VERSION 5.7 ;
  NOWIREEXTENSIONATPIN ON ;
  DIVIDERCHAR "/" ;
  BUSBITCHARS "[]" ;
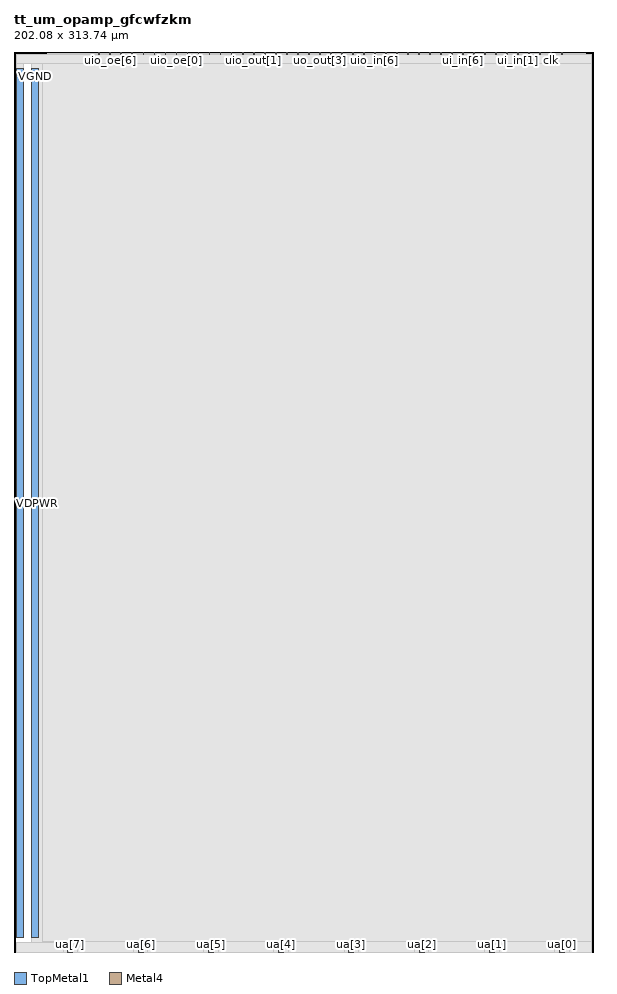
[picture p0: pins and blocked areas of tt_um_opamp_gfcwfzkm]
MACRO tt_um_opamp_gfcwfzkm
  CLASS BLOCK ;
  FOREIGN tt_um_opamp_gfcwfzkm ;
  ORIGIN 0.000 0.000 ;
  SIZE 202.080 BY 313.740 ;
  PIN ua[0]
    ANTENNAGATEAREA 1499.839966 ;
    ANTENNADIFFAREA 474.417999 ;
    PORT
      LAYER TopMetal1 ;
        RECT 190.165 0.000 191.915 2.000 ;
    END
  END ua[0]
  PIN ua[1]
    ANTENNAGATEAREA 2.160000 ;
    ANTENNADIFFAREA 147.899994 ;
    PORT
      LAYER TopMetal1 ;
        RECT 165.685 0.000 167.435 2.000 ;
    END
  END ua[1]
  PIN ua[2]
    ANTENNAGATEAREA 4.320000 ;
    PORT
      LAYER TopMetal1 ;
        RECT 141.205 0.000 142.955 2.000 ;
    END
  END ua[2]
  PIN ua[3]
    PORT
      LAYER TopMetal1 ;
        RECT 116.725 0.000 118.475 2.000 ;
    END
  END ua[3]
  PIN ua[4]
    PORT
      LAYER TopMetal1 ;
        RECT 92.245 0.000 93.995 2.000 ;
    END
  END ua[4]
  PIN ua[5]
    PORT
      LAYER TopMetal1 ;
        RECT 67.765 0.000 69.515 2.000 ;
    END
  END ua[5]
  PIN ua[6]
    PORT
      LAYER TopMetal1 ;
        RECT 43.285 0.000 45.035 2.000 ;
    END
  END ua[6]
  PIN ua[7]
    PORT
      LAYER TopMetal1 ;
        RECT 18.805 0.000 20.555 2.000 ;
    END
  END ua[7]
  PIN VDPWR
    ANTENNADIFFAREA 31.673199 ;
    PORT
      LAYER TopMetal1 ;
        RECT 1.000 5.000 3.400 308.000 ;
    END
  END VDPWR
  PIN VGND
    ANTENNAGATEAREA 168.959991 ;
    ANTENNADIFFAREA 1001.514404 ;
    PORT
      LAYER TopMetal1 ;
        RECT 6.000 5.000 8.400 308.000 ;
    END
  END VGND
  PIN clk
    PORT
      LAYER Metal4 ;
        RECT 187.050 312.740 187.350 313.740 ;
    END
  END clk
  PIN ena
    PORT
      LAYER Metal4 ;
        RECT 190.890 312.740 191.190 313.740 ;
    END
  END ena
  PIN rst_n
    PORT
      LAYER Metal4 ;
        RECT 183.210 312.740 183.510 313.740 ;
    END
  END rst_n
  PIN ui_in[0]
    ANTENNAGATEAREA 0.058500 ;
    PORT
      LAYER Metal4 ;
        RECT 179.370 312.740 179.670 313.740 ;
    END
  END ui_in[0]
  PIN ui_in[1]
    ANTENNAGATEAREA 0.058500 ;
    PORT
      LAYER Metal4 ;
        RECT 175.530 312.740 175.830 313.740 ;
    END
  END ui_in[1]
  PIN ui_in[2]
    ANTENNAGATEAREA 0.058500 ;
    PORT
      LAYER Metal4 ;
        RECT 171.690 312.740 171.990 313.740 ;
    END
  END ui_in[2]
  PIN ui_in[3]
    ANTENNAGATEAREA 0.058500 ;
    PORT
      LAYER Metal4 ;
        RECT 167.850 312.740 168.150 313.740 ;
    END
  END ui_in[3]
  PIN ui_in[4]
    ANTENNAGATEAREA 0.058500 ;
    PORT
      LAYER Metal4 ;
        RECT 164.010 312.740 164.310 313.740 ;
    END
  END ui_in[4]
  PIN ui_in[5]
    ANTENNAGATEAREA 0.058500 ;
    PORT
      LAYER Metal4 ;
        RECT 160.170 312.740 160.470 313.740 ;
    END
  END ui_in[5]
  PIN ui_in[6]
    ANTENNAGATEAREA 0.058500 ;
    PORT
      LAYER Metal4 ;
        RECT 156.330 312.740 156.630 313.740 ;
    END
  END ui_in[6]
  PIN ui_in[7]
    ANTENNAGATEAREA 0.058500 ;
    PORT
      LAYER Metal4 ;
        RECT 152.490 312.740 152.790 313.740 ;
    END
  END ui_in[7]
  PIN uio_in[0]
    ANTENNAGATEAREA 0.058500 ;
    PORT
      LAYER Metal4 ;
        RECT 148.650 312.740 148.950 313.740 ;
    END
  END uio_in[0]
  PIN uio_in[1]
    ANTENNAGATEAREA 0.058500 ;
    PORT
      LAYER Metal4 ;
        RECT 144.810 312.740 145.110 313.740 ;
    END
  END uio_in[1]
  PIN uio_in[2]
    PORT
      LAYER Metal4 ;
        RECT 140.970 312.740 141.270 313.740 ;
    END
  END uio_in[2]
  PIN uio_in[3]
    PORT
      LAYER Metal4 ;
        RECT 137.130 312.740 137.430 313.740 ;
    END
  END uio_in[3]
  PIN uio_in[4]
    PORT
      LAYER Metal4 ;
        RECT 133.290 312.740 133.590 313.740 ;
    END
  END uio_in[4]
  PIN uio_in[5]
    PORT
      LAYER Metal4 ;
        RECT 129.450 312.740 129.750 313.740 ;
    END
  END uio_in[5]
  PIN uio_in[6]
    PORT
      LAYER Metal4 ;
        RECT 125.610 312.740 125.910 313.740 ;
    END
  END uio_in[6]
  PIN uio_in[7]
    PORT
      LAYER Metal4 ;
        RECT 121.770 312.740 122.070 313.740 ;
    END
  END uio_in[7]
  PIN uio_oe[0]
    ANTENNADIFFAREA 0.272000 ;
    PORT
      LAYER Metal4 ;
        RECT 56.490 312.740 56.790 313.740 ;
    END
  END uio_oe[0]
  PIN uio_oe[1]
    ANTENNADIFFAREA 0.272000 ;
    PORT
      LAYER Metal4 ;
        RECT 52.650 312.740 52.950 313.740 ;
    END
  END uio_oe[1]
  PIN uio_oe[2]
    ANTENNADIFFAREA 0.272000 ;
    PORT
      LAYER Metal4 ;
        RECT 48.810 312.740 49.110 313.740 ;
    END
  END uio_oe[2]
  PIN uio_oe[3]
    ANTENNADIFFAREA 0.272000 ;
    PORT
      LAYER Metal4 ;
        RECT 44.970 312.740 45.270 313.740 ;
    END
  END uio_oe[3]
  PIN uio_oe[4]
    ANTENNADIFFAREA 0.272000 ;
    PORT
      LAYER Metal4 ;
        RECT 41.130 312.740 41.430 313.740 ;
    END
  END uio_oe[4]
  PIN uio_oe[5]
    ANTENNADIFFAREA 0.272000 ;
    PORT
      LAYER Metal4 ;
        RECT 37.290 312.740 37.590 313.740 ;
    END
  END uio_oe[5]
  PIN uio_oe[6]
    ANTENNADIFFAREA 0.272000 ;
    PORT
      LAYER Metal4 ;
        RECT 33.450 312.740 33.750 313.740 ;
    END
  END uio_oe[6]
  PIN uio_oe[7]
    ANTENNADIFFAREA 0.272000 ;
    PORT
      LAYER Metal4 ;
        RECT 29.610 312.740 29.910 313.740 ;
    END
  END uio_oe[7]
  PIN uio_out[0]
    ANTENNADIFFAREA 0.272000 ;
    PORT
      LAYER Metal4 ;
        RECT 87.210 312.740 87.510 313.740 ;
    END
  END uio_out[0]
  PIN uio_out[1]
    ANTENNADIFFAREA 0.272000 ;
    PORT
      LAYER Metal4 ;
        RECT 83.370 312.740 83.670 313.740 ;
    END
  END uio_out[1]
  PIN uio_out[2]
    ANTENNADIFFAREA 0.272000 ;
    PORT
      LAYER Metal4 ;
        RECT 79.530 312.740 79.830 313.740 ;
    END
  END uio_out[2]
  PIN uio_out[3]
    ANTENNADIFFAREA 0.272000 ;
    PORT
      LAYER Metal4 ;
        RECT 75.690 312.740 75.990 313.740 ;
    END
  END uio_out[3]
  PIN uio_out[4]
    ANTENNADIFFAREA 0.272000 ;
    PORT
      LAYER Metal4 ;
        RECT 71.850 312.740 72.150 313.740 ;
    END
  END uio_out[4]
  PIN uio_out[5]
    ANTENNADIFFAREA 0.272000 ;
    PORT
      LAYER Metal4 ;
        RECT 68.010 312.740 68.310 313.740 ;
    END
  END uio_out[5]
  PIN uio_out[6]
    ANTENNADIFFAREA 0.272000 ;
    PORT
      LAYER Metal4 ;
        RECT 64.170 312.740 64.470 313.740 ;
    END
  END uio_out[6]
  PIN uio_out[7]
    ANTENNADIFFAREA 0.272000 ;
    PORT
      LAYER Metal4 ;
        RECT 60.330 312.740 60.630 313.740 ;
    END
  END uio_out[7]
  PIN uo_out[0]
    ANTENNADIFFAREA 0.306000 ;
    PORT
      LAYER Metal4 ;
        RECT 117.930 312.740 118.230 313.740 ;
    END
  END uo_out[0]
  PIN uo_out[1]
    ANTENNADIFFAREA 0.306000 ;
    PORT
      LAYER Metal4 ;
        RECT 114.090 312.740 114.390 313.740 ;
    END
  END uo_out[1]
  PIN uo_out[2]
    ANTENNADIFFAREA 0.306000 ;
    PORT
      LAYER Metal4 ;
        RECT 110.250 312.740 110.550 313.740 ;
    END
  END uo_out[2]
  PIN uo_out[3]
    ANTENNADIFFAREA 0.306000 ;
    PORT
      LAYER Metal4 ;
        RECT 106.410 312.740 106.710 313.740 ;
    END
  END uo_out[3]
  PIN uo_out[4]
    ANTENNADIFFAREA 0.272000 ;
    PORT
      LAYER Metal4 ;
        RECT 102.570 312.740 102.870 313.740 ;
    END
  END uo_out[4]
  PIN uo_out[5]
    ANTENNADIFFAREA 0.272000 ;
    PORT
      LAYER Metal4 ;
        RECT 98.730 312.740 99.030 313.740 ;
    END
  END uo_out[5]
  PIN uo_out[6]
    ANTENNADIFFAREA 0.272000 ;
    PORT
      LAYER Metal4 ;
        RECT 94.890 312.740 95.190 313.740 ;
    END
  END uo_out[6]
  PIN uo_out[7]
    ANTENNADIFFAREA 0.306000 ;
    PORT
      LAYER Metal4 ;
        RECT 91.050 312.740 91.350 313.740 ;
    END
  END uo_out[7]
  OBS
      LAYER GatPoly ;
        RECT 11.605 5.030 196.055 310.965 ;
      LAYER Metal1 ;
        RECT 11.605 5.030 196.280 313.045 ;
      LAYER Metal2 ;
        RECT 12.545 5.570 195.020 313.045 ;
      LAYER Metal3 ;
        RECT 14.440 0.320 199.150 313.045 ;
      LAYER Metal4 ;
        RECT 14.435 312.530 29.400 313.045 ;
        RECT 30.120 312.530 33.240 313.045 ;
        RECT 33.960 312.530 37.080 313.045 ;
        RECT 37.800 312.530 40.920 313.045 ;
        RECT 41.640 312.530 44.760 313.045 ;
        RECT 45.480 312.530 48.600 313.045 ;
        RECT 49.320 312.530 52.440 313.045 ;
        RECT 53.160 312.530 56.280 313.045 ;
        RECT 57.000 312.530 60.120 313.045 ;
        RECT 60.840 312.530 63.960 313.045 ;
        RECT 64.680 312.530 67.800 313.045 ;
        RECT 68.520 312.530 71.640 313.045 ;
        RECT 72.360 312.530 75.480 313.045 ;
        RECT 76.200 312.530 79.320 313.045 ;
        RECT 80.040 312.530 83.160 313.045 ;
        RECT 83.880 312.530 87.000 313.045 ;
        RECT 87.720 312.530 90.840 313.045 ;
        RECT 91.560 312.530 94.680 313.045 ;
        RECT 95.400 312.530 98.520 313.045 ;
        RECT 99.240 312.530 102.360 313.045 ;
        RECT 103.080 312.530 106.200 313.045 ;
        RECT 106.920 312.530 110.040 313.045 ;
        RECT 110.760 312.530 113.880 313.045 ;
        RECT 114.600 312.530 117.720 313.045 ;
        RECT 118.440 312.530 121.560 313.045 ;
        RECT 122.280 312.530 125.400 313.045 ;
        RECT 126.120 312.530 129.240 313.045 ;
        RECT 129.960 312.530 133.080 313.045 ;
        RECT 133.800 312.530 136.920 313.045 ;
        RECT 137.640 312.530 140.760 313.045 ;
        RECT 141.480 312.530 144.600 313.045 ;
        RECT 145.320 312.530 148.440 313.045 ;
        RECT 149.160 312.530 152.280 313.045 ;
        RECT 153.000 312.530 156.120 313.045 ;
        RECT 156.840 312.530 159.960 313.045 ;
        RECT 160.680 312.530 163.800 313.045 ;
        RECT 164.520 312.530 167.640 313.045 ;
        RECT 168.360 312.530 171.480 313.045 ;
        RECT 172.200 312.530 175.320 313.045 ;
        RECT 176.040 312.530 179.160 313.045 ;
        RECT 179.880 312.530 183.000 313.045 ;
        RECT 183.720 312.530 186.840 313.045 ;
        RECT 187.560 312.530 190.680 313.045 ;
        RECT 191.400 312.530 194.500 313.045 ;
        RECT 14.435 0.540 194.500 312.530 ;
      LAYER Metal5 ;
        RECT 6.000 0.000 201.405 309.930 ;
      LAYER TopMetal1 ;
        RECT 1.000 309.640 201.405 313.025 ;
        RECT 1.000 308.000 3.400 309.640 ;
        RECT 10.040 3.640 201.405 309.640 ;
        RECT 10.040 3.360 17.165 3.640 ;
        RECT 1.000 0.000 17.165 3.360 ;
        RECT 22.195 0.000 41.645 3.640 ;
        RECT 46.675 0.000 66.125 3.640 ;
        RECT 71.155 0.000 90.605 3.640 ;
        RECT 95.635 0.000 115.085 3.640 ;
        RECT 120.115 0.000 139.565 3.640 ;
        RECT 144.595 0.000 164.045 3.640 ;
        RECT 169.075 0.000 188.525 3.640 ;
        RECT 193.555 0.000 201.405 3.640 ;
  END
END tt_um_opamp_gfcwfzkm
END LIBRARY

